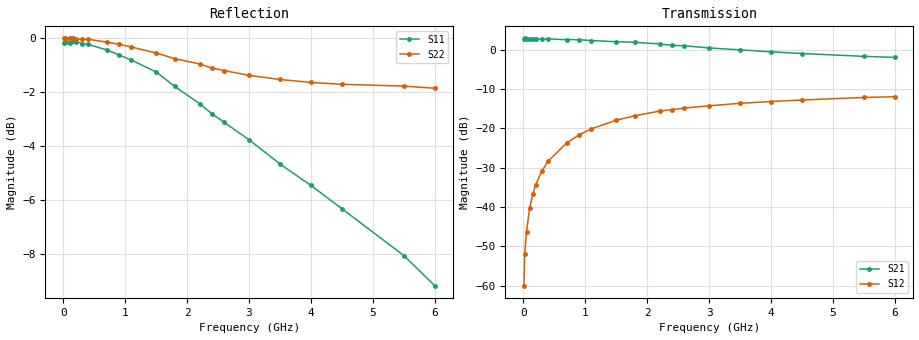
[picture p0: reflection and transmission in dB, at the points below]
! SIEMENS Discrete & RF Semiconductors
! BFY180
! Si NPN RF Bipolar Junction Transistor in MICRO-X
! VCE = 3.5 V  IC = 0.4 mA
! Common Emitter S-Parameters:  May  1997
# GHz  S  MA  R  50
!  f  S11  S21  S12  S22
! GHz  MAG  ANG  MAG  ANG  MAG  ANG  MAG  ANG
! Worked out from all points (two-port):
!   36 points, 10 MHz to 6 GHz, reference 50 ohm
!   highest |S21| = 2.89 dB at 20 MHz (marker M1); lowest = -1.9 dB at 6 GHz (marker M2)
!   |S21| within 3 dB of the highest: start of sweep to 3.582 GHz
!   lowest |S11| = -9.2 dB at 6 GHz (marker M3), VSWR 2.06, Z = 28.1 - j17.1 ohm
!   |S11| at or under -10 dB: nowhere
!   |S22| runs from -1.9 to 0.0 dB; largest |S21 - S12| = 1.4
!   S11 on the Smith chart (normalised r, x): 10 MHz: open; 700 MHz: 0.73, -5.27; 1.5 GHz: 0.51, -2.41; 2.4 GHz: 0.51, -1.41; 4 GHz: 0.52, -0.76; 6 GHz: 0.56, -0.34
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0.01  0.9812 -0.2  1.377 179.8  0.001 87.0  0.9995 -0.2
0.02  0.9875 -0.4  1.395 179.2  0.0025 88.4  0.9999 -0.5
0.05  0.9854 -1.5  1.38 178.2  0.0048 83.8  0.9981 -1.1
0.1  0.9814 -3.1  1.387 176.3  0.0096 88.3  0.9996 -2.2
0.15  0.9879 -4.9  1.375 174.4  0.0145 87.4  0.9996 -3.3
0.2  0.9861 -6.0  1.376 172.1  0.0193 85.7  0.9979 -4.3
0.3  0.9781 -9.0  1.366 168.1  0.0288 82.4  0.9959 -6.5
0.4  0.9744 -12.0  1.373 164.2  0.0384 80.8  0.9959 -8.7
0.7  0.9517 -21.1  1.343 152.8  0.0653 73.1  0.984 -15.1
0.9  0.9315 -26.8  1.34 145.1  0.0827 68.1  0.9749 -19.3
1.1  0.9111 -32.5  1.309 137.9  0.0986 63.8  0.9635 -23.4
1.5  0.8658 -43.6  1.264 123.8  0.1273 54.9  0.9393 -31.4
1.8  0.8139 -52.1  1.246 113.0  0.1446 49.3  0.9166 -36.9
2.2  0.7564 -61.3  1.183 99.8  0.1661 41.8  0.8962 -43.8
2.4  0.7244 -66.2  1.139 93.6  0.173 38.6  0.8807 -47.0
2.6  0.698 -70.5  1.124 87.8  0.1812 35.7  0.8712 -49.9
3  0.648 -78.4  1.054 77.1  0.1938 30.0  0.8534 -55.8
3.5  0.5842 -87.0  0.997 64.2  0.2083 24.0  0.8386 -62.6
4  0.5331 -95.6  0.941 52.7  0.2196 18.3  0.828 -69.4
4.5  0.4825 -103.4  0.895 42.3  0.2294 13.3  0.8216 -76.2
5.5  0.395 -120.1  0.824 22.9  0.2472 3.4  0.8152 -90.2
6  0.3472 -129.7  0.799 14.0  0.2527 -1.5  0.8079 -97.2
